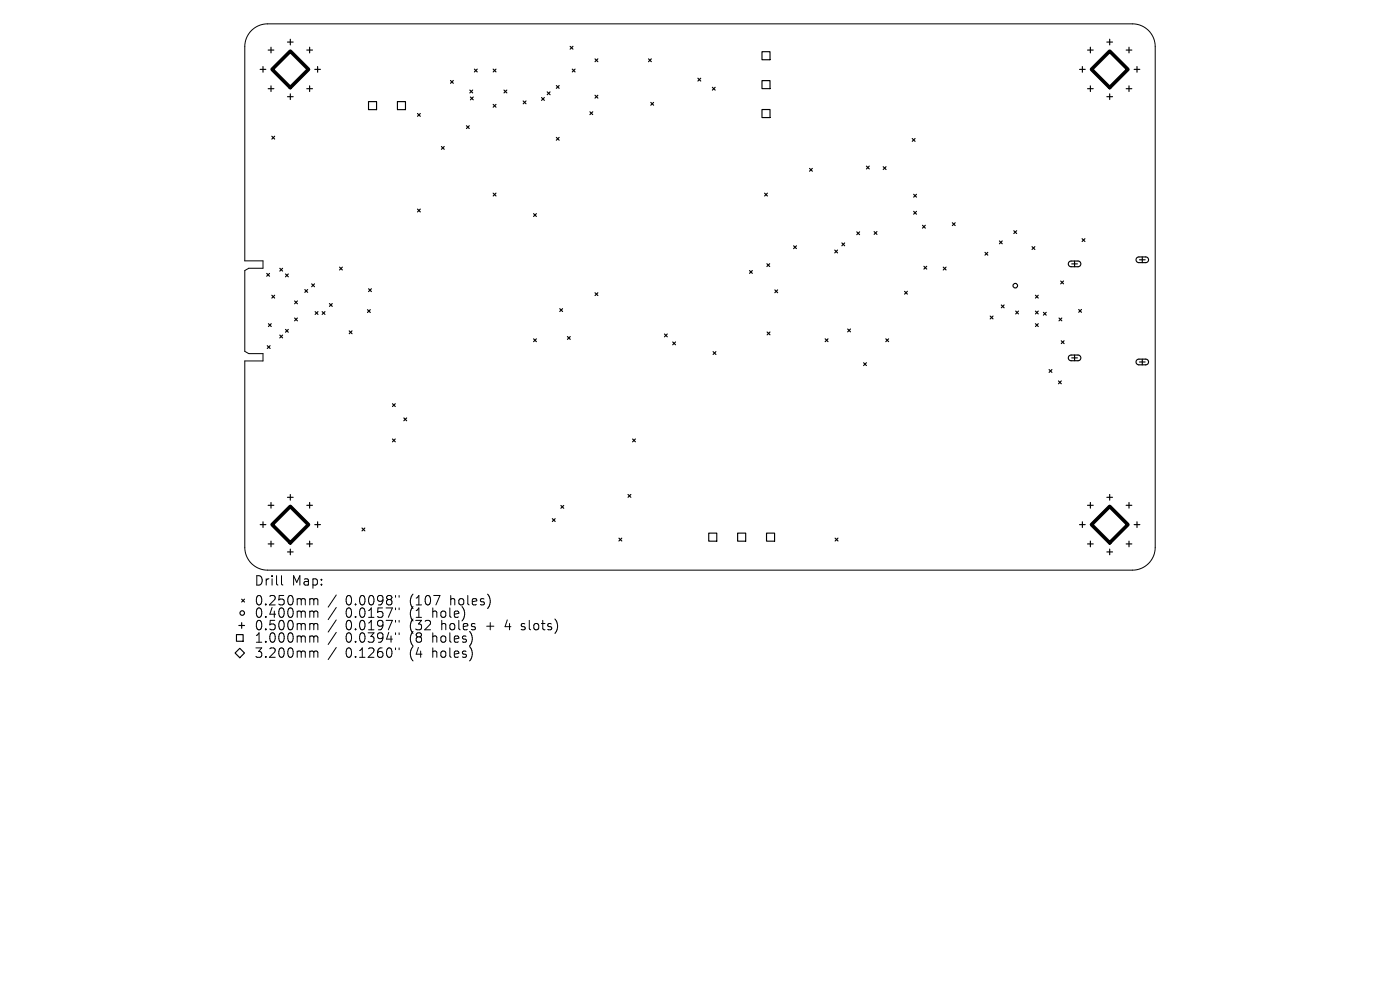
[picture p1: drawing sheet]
<svg xmlns="http://www.w3.org/2000/svg" width="297mm" height="210mm" viewBox="0 0 297 210" stroke-linecap="round" stroke-linejoin="round" font-family="sans-serif">
<defs><g id="words">
<g font-size="2.8">
<text x="53.9" y="124.5">Drill</text>
<text x="61.9" y="124.5">Map:</text>
<text x="53.9" y="128.7">0.250mm</text>
<text x="53.9" y="131.3">0.400mm</text>
<text x="73.3" y="128.7">0.0098&quot;</text>
<text x="73.3" y="131.3">0.0157&quot;</text>
<text x="87" y="128.7">(107</text>
<text x="87" y="131.3">(1</text>
<text x="92" y="131.3">hole)</text>
<text x="95.8" y="128.7">holes)</text>
<text x="53.9" y="134">0.500mm</text>
<text x="53.9" y="136.6">1.000mm</text>
<text x="73.3" y="134">0.0197&quot;</text>
<text x="73.3" y="136.6">0.0394&quot;</text>
<text x="87" y="134">(32</text>
<text x="87" y="136.6">(8</text>
<text x="92" y="136.6">holes)</text>
<text x="93.9" y="134">holes</text>
<text x="103.6" y="134">+</text>
<text x="107.8" y="134">4</text>
<text x="111.5" y="134">slots)</text>
<text x="53.9" y="139.8">3.200mm</text>
<text x="73.3" y="139.8">0.1260&quot;</text>
<text x="87" y="139.8">(4</text>
<text x="92" y="139.8">holes)</text>
</g>
</g></defs>
<g fill="none" stroke="#000" stroke-width=".21">
<path d="M53.3 6.5a4.8 4.8 0 0 1 3.5-1.4h183.4a4.8 4.8 0 0 1 4.9 4.8v106.2a4.8 4.8 0 0 1-4.9 4.8h-183.4a4.8 4.8 0 0 1-4.9-4.8v-39.5h3.9v-1.6h-3l-.9-.5v-17.1l.9-.5h3v-1.6h-3.9v-45.4a4.8 4.8 0 0 1 1.4-3.4zM59.7 122.1v1.7l.3 .3M66 127l.5 .1 .1 .2M66 129.6h.3l.3 .3M66 132.3l.5 .1 .1 .2M66 134.9l.5 .1 .1 .2M66 138.1l.5 .1 .1 .2M66.6 127.3l.3-.3 .4 .1 .1 1.2M66.6 127.3v1M66.6 129.9v1.1M66.6 132.6v1M66.6 135.2v1"/>
<path d="M66.6 138.4v1M66.6 129.9l.3-.3 .4 .1 .1 1.3M66.6 132.6l.3-.3 .4 .1 .1 1.2M66.6 135.2l.3-.3 .4 .1 .1 1.2M66.6 138.4l.3-.3 .4 .1 .1 1.2M71.3 126.2l-1.7 2.6M71.3 128.9l-1.7 2.5M71.3 131.5l-1.7 2.6M71.3 134.1l-1.7 2.6M71.3 137.3l-1.7 2.6M83.9 126.3v.4M83.9 129v.3"/>
<path d="M83.9 131.6v.4M83.9 134.2v.4M83.9 137.4v.4M84.7 126.3v.4M84.7 129v.3M84.7 131.6v.4M84.7 134.2v.4M84.7 137.4v.4M110.6 133.5l.2 .1M110.7 132.4v.4"/>
</g>
<g fill="none" stroke="#000" stroke-width=".24">
<path d="M55.2 14.7h1.2M55.8 14.1v1.2M56.9 10.6h1.2M56.9 18.8h1.2M57.5 10v1.2M57.5 18.2v1.2M61 8.9h1.2M61.6 8.3v1.2M61.6 19.9v1.2M65.1 10.6h1.2M65.1 18.8h1.2M65.7 10v1.2"/>
<path d="M65.7 18.2v1.2M66.8 14.7h1.2M67.4 14.1v1.2M95.6 17.1l.6 .6M96.2 17.1l-.6 .6M99.7 19.1l.6 .6M100.3 19.1l-.6 .6M100.6 14.7l.6 .6M101.2 14.7l-.6 .6M104.6 14.7l.6 .6M105.2 14.7l-.6 .6M106.9 19.1l.6 .6"/>
<path d="M107.5 19.1l-.6 .6M116.1 19.5l.6 .6M116.7 19.5l-.6 .6M118 18.1l.6 .6M118.6 18.1l-.6 .6M120.9 9.8l.7 .6M121.4 14.7l.6 .6M121.6 9.8l-.7 .6M122 14.7l-.6 .6M126.2 12.5l.6 .6M126.8 12.5l-.6 .6M137.6 12.5l.6 .6"/>
<path d="M138.2 12.5l-.6 .6M148.1 16.6l.6 .6M148.7 16.6l-.6 .6M151.1 18.5l.6 .6M151.7 18.5l-.6 .6M161.7 11h1.7v1.7h-1.7zM161.7 17.1h1.7v1.7h-1.7zM229 14.7h1.2M229.6 14.1v1.2M230.7 10.6h1.2M230.7 18.8h1.2M231.3 10v1.2"/>
<path d="M231.3 18.2v1.2M234.8 8.9h1.2M235.4 8.3v1.2M235.4 19.9v1.2M238.9 10.6h1.2M238.9 18.8h1.2M239.5 10v1.2M239.5 18.2v1.2M240.6 14.7h1.2M241.2 14.1v1.2M57.7 28.9l.6 .6M58.3 28.9l-.6 .6"/>
<path d="M61 20.5h1.2M78.2 21.6h1.7v1.7h-1.7zM84.3 21.6h1.7v1.7h-1.7zM88.6 24.1l.6 .6M89.2 24.1l-.6 .6M93.6 31.1l.6 .6M94.2 31.1l-.6 .6M98.9 26.7l.7 .6M99.6 26.7l-.7 .6M99.8 20.6l.6 .6M100.4 20.6l-.6 .6M104.6 22.1l.6 .6"/>
<path d="M105.2 22.1l-.6 .6M111 21.4l.6 .6M111.6 21.4l-.6 .6M114.9 20.7l.6 .6M115.5 20.7l-.6 .6M118 29.1l.6 .6M118.6 29.1l-.6 .6M125.1 23.7l.6 .6M125.7 23.7l-.6 .6M126.2 20.2l.6 .6M126.8 20.2l-.6 .6M138.1 21.7l.6 .6"/>
<path d="M138.7 21.7l-.6 .6M161.7 23.2h1.7v1.7h-1.7zM171.7 35.7l.6 .6M172.3 35.7l-.6 .6M183.8 35.2l.6 .6M184.4 35.2l-.6 .6M187.4 35.4l.6 .6M188 35.4l-.6 .6M193.5 29.4l.6 .6M194.1 29.4l-.6 .6M234.8 20.5h1.2M56.6 58l.6 .6"/>
<path d="M57.2 58l-.6 .6M59.4 56.9l.6 .6M60 56.9l-.6 .6M60.6 58.1l.6 .6M61.2 58.1l-.6 .6M72 56.7l.6 .6M72.6 56.7l-.6 .6M88.6 44.4l.6 .6M89.2 44.4l-.6 .6M104.6 41l.6 .6M105.2 41l-.6 .6M113.2 45.3l.6 .6"/>
<path d="M113.8 45.3l-.6 .6M159 57.4l.6 .6M159.6 57.4l-.6 .6M162.2 41l.6 .6M162.7 55.9l.6 .6M162.8 41l-.6 .6M163.3 55.9l-.6 .6M168.4 52.1l.6 .6M169 52.1l-.6 .6M177.1 53l.6 .6M177.7 53l-.6 .6M178.6 51.5l.6 .6"/>
<path d="M179.2 51.5l-.6 .6M181.8 49.2l.6 .6M182.4 49.2l-.6 .6M185.4 49.1l.6 .6M186 49.1l-.6 .6M193.8 41.2l.6 .6M193.8 44.8l.6 .6M194.4 41.2l-.6 .6M194.4 44.8l-.6 .6M195.7 47.8l.6 .6M196 56.5l.6 .6M196.3 47.8l-.6 .6"/>
<path d="M196.6 56.5l-.6 .6M200.1 56.7l.6 .6M200.7 56.7l-.6 .6M202 47.2l.6 .7M202.6 47.2l-.6 .7M209 53.5l.6 .6M209.6 53.5l-.6 .6M212 51.1l.6 .6M212.6 51.1l-.6 .6M215.1 48.9l.6 .6M215.7 48.9l-.6 .6M218.9 52.3l.6 .6"/>
<path d="M219.5 52.3l-.6 .6M225 59.6l.6 .6M225.6 59.6l-.6 .6M226.8 55.6l.4-.2h1.6l.4 .3 .1 .4-.5 .5h-1.7l-.4-.5zM227.4 56h1.2M228 55.4v1.2M229.6 50.6l.6 .6M230.2 50.6l-.6 .6M241.2 54.7l.4-.2h1.6l.4 .3v.5l-.4 .4h-1.7l-.5-.4zM241.7 55.1h1.2M242.3 54.5v1.2M56.7 73.3l.6 .6"/>
<path d="M56.9 68.7l.6 .6M57.3 73.3l-.6 .6M57.5 68.7l-.6 .6M57.7 62.6l.6 .6M58.3 62.6l-.6 .6M59.4 71.1l.6 .6M60 71.1l-.6 .6M60.6 69.9l.6 .6M61.2 69.9l-.6 .6M62.5 63.8l.6 .6M62.5 67.5l.6 .6M63.1 63.8l-.6 .6"/>
<path d="M63.1 67.5l-.6 .6M64.7 61.4l.6 .6M65.3 61.4l-.6 .6M66.1 60.2l.6 .6M66.7 60.2l-.6 .6M66.9 66.1l.6 .6M67.5 66.1l-.6 .6M68.3 66.1l.6 .6M68.9 66.1l-.6 .6M69.9 64.4l.6 .6M70.5 64.4l-.6 .6M74.1 70.2l.6 .6"/>
<path d="M74.7 70.2l-.6 .6M78 65.7l.6 .6M78.2 61.3l.6 .6M78.6 65.7l-.6 .6M78.8 61.3l-.6 .6M113.2 71.9l.6 .6M113.8 71.9l-.6 .6M118.7 65.5l.6 .6M119.3 65.5l-.6 .6M120.4 71.4l.6 .6M121 71.4l-.6 .6M126.2 62.1l.6 .6"/>
<path d="M126.8 62.1l-.6 .6M141 70.8l.6 .7M141.6 70.8l-.6 .7M142.7 72.5l.6 .6M143.3 72.5l-.6 .6M151.3 74.6l.6 .6M151.9 74.6l-.6 .6M162.7 70.4l.6 .6M163.3 70.4l-.6 .6M164.4 61.5l.6 .6M165 61.5l-.6 .6M175.1 71.9l.6 .6"/>
<path d="M175.7 71.9l-.6 .6M179.8 69.8l.6 .6M180.4 69.8l-.6 .6M183.2 76.9l.6 .6M183.8 76.9l-.6 .6M187.9 71.9l.6 .6M188.5 71.9l-.6 .6M191.9 61.8l.6 .6M192.5 61.8l-.6 .6M210.1 67l.6 .6M210.7 67l-.6 .6M212.4 64.7l.6 .6"/>
<path d="M213 64.7l-.6 .6M215.5 66l.6 .6M216.1 66l-.6 .6M219.7 62.6l.6 .6M219.7 66l.6 .6M219.7 68.7l.6 .6M220.3 62.6l-.6 .6M220.3 66l-.6 .6M220.3 68.7l-.6 .6M221.4 66.2l.6 .7M222 66.2l-.6 .7M222.6 78.4l.6 .6"/>
<path d="M223.2 78.4l-.6 .6M224.7 67.5l.6 .6M225.1 72.3l.6 .6M225.3 67.5l-.6 .6M225.7 72.3l-.6 .6M226.8 75.5l.4-.2h1.6l.4 .3 .1 .5-.5 .4h-1.7l-.4-.4zM227.4 75.9h1.2M228 75.3v1.2M228.8 65.6l.6 .6M229.4 65.6l-.6 .6M241.2 76.4l.4-.2h1.6l.4 .3v.4l-.4 .5h-1.7l-.5-.5zM241.7 76.8h1.2"/>
<path d="M242.3 76.2v1.2M83.3 85.6l.6 .6M83.3 93.1l.6 .6M83.9 85.6l-.6 .6M83.9 93.1l-.6 .6M85.7 88.7l.6 .6M86.3 88.7l-.6 .6M134.2 93.1l.6 .6M134.8 93.1l-.6 .6M224.5 80.8l.7 .6M225.2 80.8l-.7 .6M55.2 111.3h1.2"/>
<path d="M55.8 110.7v1.2M56.9 107.2h1.2M56.9 115.4h1.2M57.5 106.6v1.2M57.5 114.8v1.2M61 105.5h1.2M61 117.1h1.2M61.6 104.9v1.2M61.6 116.5v1.2M65.1 107.2h1.2M65.1 115.4h1.2M65.7 106.6v1.2"/>
<path d="M65.7 114.8v1.2M66.8 111.3h1.2M67.4 110.7v1.2M76.8 112l.6 .6M77.4 112l-.6 .6M117.2 110l.6 .6M117.8 110l-.6 .6M119 107.2l.6 .6M119.6 107.2l-.6 .6M131.3 114.2l.6 .6M131.9 114.2l-.6 .6M133.2 104.9l.6 .6"/>
<path d="M133.8 104.9l-.6 .6M150.4 113.1h1.7v1.7h-1.7zM156.5 113.1h1.7v1.7h-1.7zM162.6 113.1h1.7v1.7h-1.7zM177.2 114.2l.6 .6M177.8 114.2l-.6 .6M229 111.3h1.2M229.6 110.7v1.2M230.7 107.2h1.2M230.7 115.4h1.2M231.3 106.6v1.2M231.3 114.8v1.2"/>
<path d="M234.8 105.5h1.2M234.8 117.1h1.2M235.4 104.9v1.2M235.4 116.5v1.2M238.9 107.2h1.2M238.9 115.4h1.2M239.5 106.6v1.2M239.5 114.8v1.2M240.6 111.3h1.2M241.2 110.7v1.2M49.9 138.5l1-1 1 1-1 1zM50.2 134.6h1.4v1.4h-1.4z"/>
<path d="M50.7 132.7h1.2M51.3 127.1l.6 .6M51.3 132.1v1.2M51.9 127.1l-.6 .6"/>
<circle cx="215.4" cy="60.6" r=".48"/>
<circle cx="51.4" cy="130" r=".48"/>
</g>
<path d="M57.7 14.7l3.9-3.8 3.9 3.8-3.9 3.9zM231.6 14.7l3.8-3.8 3.9 3.8-3.9 3.9zM57.7 111.3l3.9-3.9 3.9 3.9-3.9 3.8zM231.6 111.3l3.8-3.9 3.9 3.9-3.9 3.8z" fill="none" stroke="#000" stroke-width=".77"/>
<use href="#words"/>
</svg>
